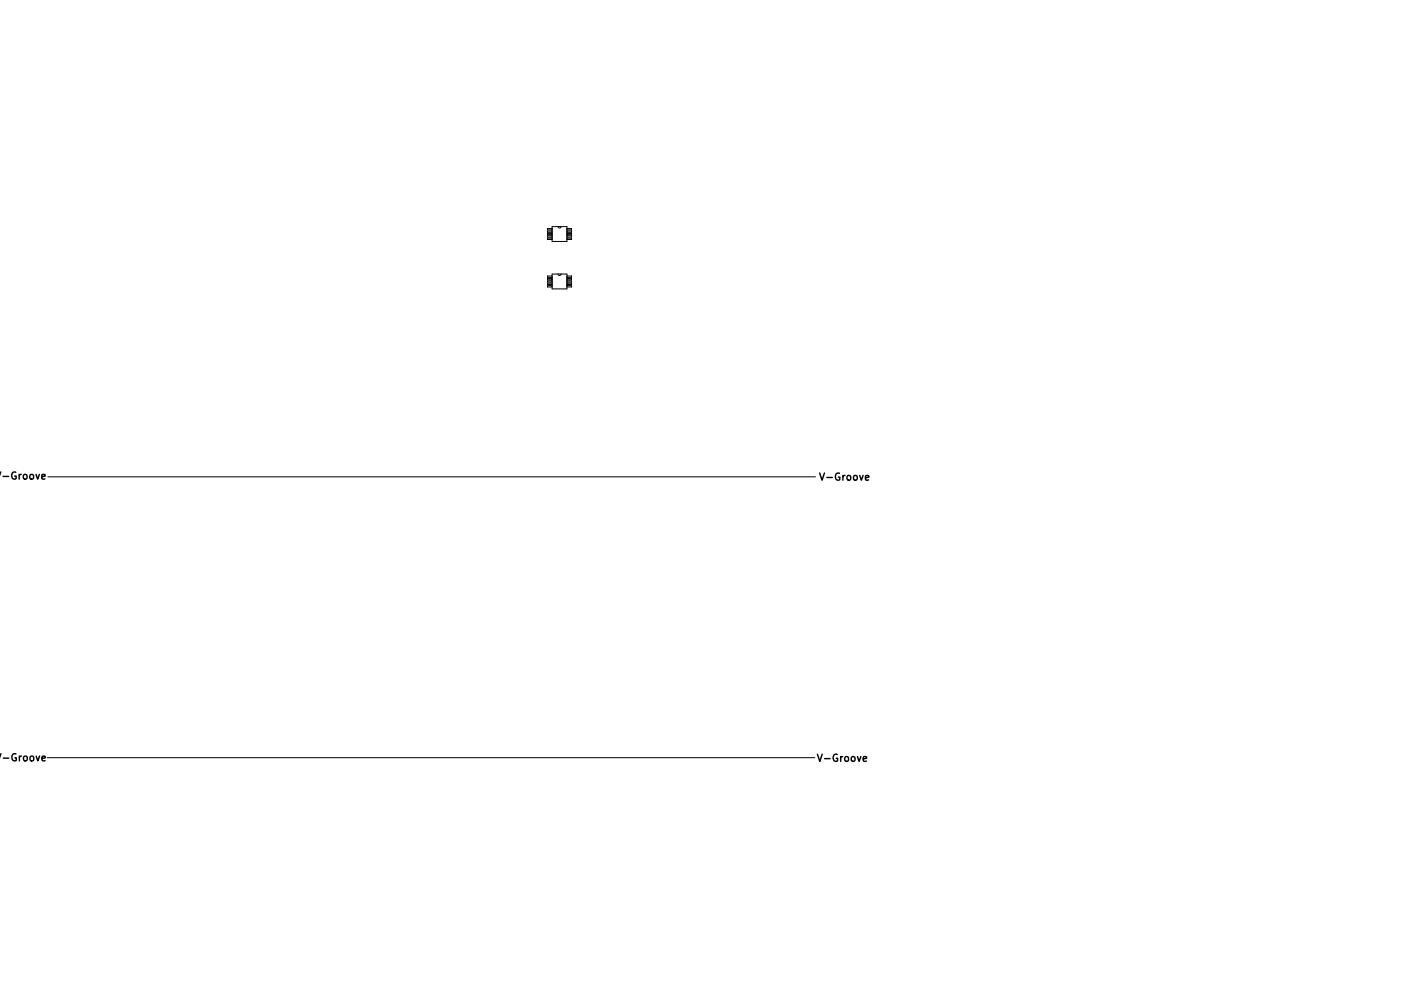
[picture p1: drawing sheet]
<svg xmlns="http://www.w3.org/2000/svg" width="297mm" height="210mm" viewBox="0 0 297 210" stroke-linecap="round" stroke-linejoin="round" font-family="sans-serif">
<defs><g id="words">
<g font-size="2.1">
<text x="-.3" y="100.1">V-Groove</text>
<text x="171.7" y="100.3">V-Groove</text>
<text x="-.3" y="158.9">V-Groove</text>
<text x="171.3" y="159">V-Groove</text>
</g>
</g></defs>
<g fill="none" stroke="#000" stroke-width=".21">
<path d="M115.3 47.3h3.1v3.1h-3.1zM115.3 57.2h3.1v3.1h-3.1zM115.3 47.7h-.9v.3h.9M115.3 48.2h-.9v.3h.9M115.3 48.7h-.9v.3h.9M115.3 49.2h-.9v.3h.9M115.3 49.7h-.9v.3h.9M115.3 57.6h-.9v.3h.9M115.3 58.1h-.9v.3h.9M115.3 58.6h-.9v.3h.9M115.3 59.1h-.9v.3h.9M115.3 59.6h-.9v.3h.9"/>
<path d="M116.6 47.3l.3 .3 .3-.3M116.6 57.2l.3 .3 .3-.3M118.4 47.7h1v.3h-1M118.4 48.2h1v.3h-1M118.4 48.7h1v.3h-1M118.4 49.2h1v.3h-1M118.4 49.7h1v.3h-1M118.4 57.6h1v.3h-1M118.4 58.1h1v.3h-1M118.4 58.6h1v.3h-1M118.4 59.1h1v.3h-1M118.4 59.6h1v.3h-1"/>
<path d="M10 99.6h160.3M9.9 158.2h160.3"/>
</g>
<use href="#words"/>
</svg>
